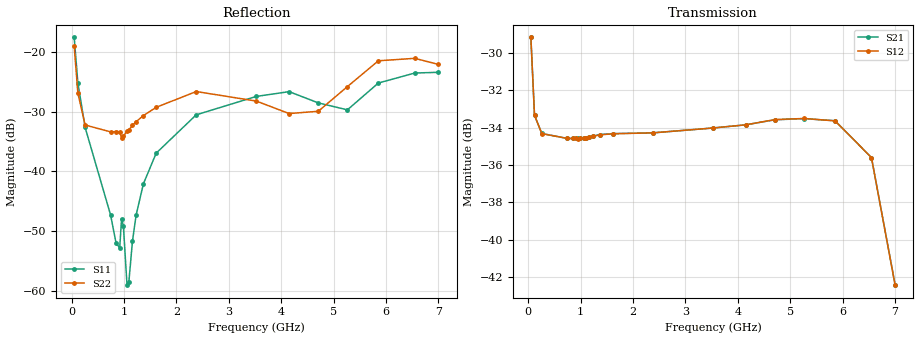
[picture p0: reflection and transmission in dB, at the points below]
! Integrated Device Technology
! Corporate Headquarters
! 6024 Silver Creek Valley Road
! San Jose, CA 95138  USA
! Phone:  1-408-284-8200
! Toll Free:  1-800-223-1366
! Webpage:  http://www.idt.com/
! Timing and RF Division
! 515 Groton Road, Suite 102
! Westford, MA 01886-6024
! Device:  F2258
! Description: Voltage Variable RF Attenuator
! Frequency:  50.0 -  6000.00 MHz
! Package:  3x3 mm Thin QFN Plastic Package: 16 pin
! Ports:  2 RF, 2 DC
!  Pin  1  = NC
!  Pin  2  = NC
!  Pin  3  = RF2  = Port 2
!  Pin  4  = GND
!  Pin  5  = Vdd
!  Pin  6  = NC
!  Pin  7  = VCTRL
!  Pin  8  = NC
!  Pin  9  = GND
!  Pin 10  = RF1  = Port 1
!  Pin 11  = NC
!  Pin 12  = NC
!  Pin 13  = NC
!  Pin 14  = NC
!  Pin 15  = NC
!  Pin 16  = NC
! Vcntrl:  1.910 Volts
! Vdd:  +3.300 Volts
! Current:  1.154 mA
! Data:  The device was measured on a the F2258 evaluation board which has
!  individual transmission lines to the RF pins.  Data was collected
!  using a calibrated network analyzer.  The evaluation board was
!  de-embedded using a TRL calibration technique.
!  The reference plane is the edge of the package pin.
! Misc:  SN 10
!  Action Tracker AT0285
! Date Measured:  2014-12-10
! Date:  2016-01-13  MJV
! Note:
!  Integrated Device Technology supplies this data as a sample of measured
!  data at the package pin for this product.  Your particular data for this
!  product may vary.
!  Data was taken at 25 degrees C.
!  Integrated Device Technology reserves the right to change this data at anytime.
!Freq_(GHz)  S11M_(dB)  S11P_(deg)  S21M_(dB)  S21P_(deg)  S12M_(dB)  S12P_(deg)  S22M_(dB)  S22P_(deg)
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# GHz S dB R 50
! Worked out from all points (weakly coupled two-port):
!   201 points, 50 MHz to 7 GHz, reference 50 ohm
!   highest |S21| = -29.17 dB at 50 MHz (marker M1); lowest = -42.4 dB at 7 GHz (marker M2)
!   lowest |S11| = -59.0 dB at 1.058 GHz (marker M3), VSWR 1.00, Z = 49.9 + j0.0502 ohm
!   |S11| at or under -10 dB: start of sweep to end of sweep
!   |S22| runs from -34.4 to -19.1 dB; largest |S21 - S12| = 8.1e-05
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0.05  -17.55 -110.8  -29.17 -65.0  -29.17 -65.0  -19.07 -104.5
0.1195  -25.11 -106.6  -33.34 -34.6  -33.34 -34.6  -26.88 -79.1
0.2585  -32.64 -111.4  -34.31 -17.8  -34.32 -17.8  -32.23 -46.4
0.745  -47.33 -141.5  -34.58 -9.3  -34.58 -9.3  -33.38 -1.1
0.84925  -52.04 -172.9  -34.58 -8.9  -34.58 -8.9  -33.33 2.0
0.91875  -52.78 150.5  -34.56 -8.9  -34.57 -8.8  -33.40 2.6
0.9535  -47.92 -161.8  -34.57 -8.8  -34.59 -8.8  -34.40 9.9
0.98825  -49.11 -172.8  -34.56 -8.7  -34.56 -8.7  -34.13 8.4
1.05775  -59.05 153.2  -34.54 -8.7  -34.55 -8.6  -33.24 9.1
1.0925  -58.56 113.7  -34.53 -8.7  -34.54 -8.6  -33.05 9.5
1.162  -51.65 66.8  -34.50 -8.7  -34.51 -8.7  -32.28 9.3
1.2315  -47.31 44.4  -34.46 -8.8  -34.47 -8.8  -31.67 9.3
1.3705  -42.07 36.0  -34.37 -9.4  -34.39 -9.4  -30.65 9.9
1.61375  -36.95 32.1  -34.32 -10.8  -34.33 -10.8  -29.27 9.1
2.37825  -30.52 47.8  -34.28 -14.8  -34.28 -14.8  -26.62 12.1
3.525  -27.44 91.5  -34.02 -21.8  -34.02 -21.9  -28.22 34.3
4.1505  -26.64 104.8  -33.85 -26.5  -33.85 -26.5  -30.31 43.3
4.7065  -28.52 95.6  -33.58 -31.3  -33.57 -31.4  -29.93 23.7
5.2625  -29.69 54.1  -33.52 -37.5  -33.51 -37.5  -25.80 -6.0
5.85325  -25.20 29.7  -33.63 -47.7  -33.64 -47.7  -21.47 -18.6
6.54825  -23.52 44.9  -35.60 -67.1  -35.60 -67.1  -21.06 -50.3
7  -23.40 84.3  -42.40 -63.5  -42.43 -63.1  -22.08 -126.1
